One B-rep face of a CAD part: STEP entity #314.
In plain terms, the planar face has unit normal (1, 0, 0).
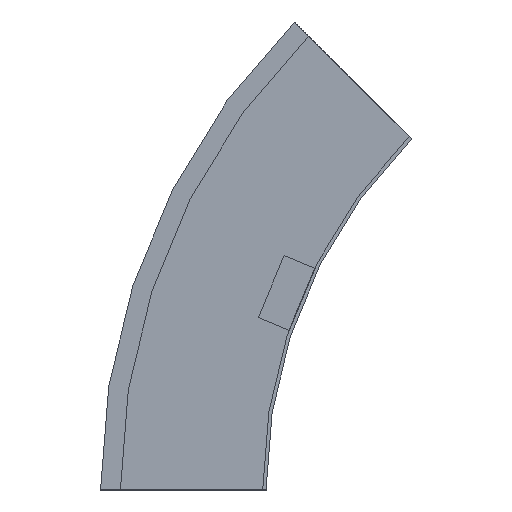
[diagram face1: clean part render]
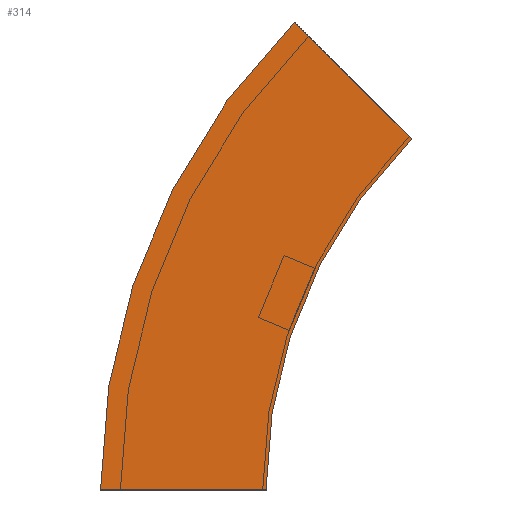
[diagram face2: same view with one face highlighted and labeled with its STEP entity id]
Its self-contained STEP definition (entity closure, numbers rounded to 3 decimals):
#16 = LINE ( 'NONE', #285, #551 ) ;
#46 = CARTESIAN_POINT ( 'NONE',  ( 0., 0., 0. ) ) ;
#48 = ORIENTED_EDGE ( 'NONE', *, *, #304, .F. ) ;
#53 = AXIS2_PLACEMENT_3D ( 'NONE', #159, #334, #133 ) ;
#73 = EDGE_LOOP ( 'NONE', ( #298, #48, #467, #95 ) ) ;
#92 = DIRECTION ( 'NONE',  ( 0., 1., 0. ) ) ;
#95 = ORIENTED_EDGE ( 'NONE', *, *, #448, .T. ) ;
#106 = CARTESIAN_POINT ( 'NONE',  ( 0., -300., 0. ) ) ;
#133 = DIRECTION ( 'NONE',  ( 0., 0., -1. ) ) ;
#159 = CARTESIAN_POINT ( 'NONE',  ( 0., 0., 0. ) ) ;
#161 = VERTEX_POINT ( 'NONE', #366 ) ;
#172 = EDGE_CURVE ( 'NONE', #510, #161, #173, .T. ) ;
#173 = CIRCLE ( 'NONE', #198, 400. ) ;
#198 = AXIS2_PLACEMENT_3D ( 'NONE', #370, #544, #543 ) ;
#210 = CIRCLE ( 'NONE', #527, 300. ) ;
#285 = CARTESIAN_POINT ( 'NONE',  ( 0., -87.868, 212.132 ) ) ;
#298 = ORIENTED_EDGE ( 'NONE', *, *, #172, .T. ) ;
#304 = EDGE_CURVE ( 'NONE', #531, #161, #16, .T. ) ;
#314 = ADVANCED_FACE ( 'NONE', ( #415 ), #376, .T. ) ;
#324 = CARTESIAN_POINT ( 'NONE',  ( 0., -87.868, 212.132 ) ) ;
#334 = DIRECTION ( 'NONE',  ( 1., 0., 0. ) ) ;
#339 = DIRECTION ( 'NONE',  ( 0., 0.707, 0.707 ) ) ;
#366 = CARTESIAN_POINT ( 'NONE',  ( 0., -17.157, 282.843 ) ) ;
#370 = CARTESIAN_POINT ( 'NONE',  ( 0., -300., 0. ) ) ;
#376 = PLANE ( 'NONE',  #53 ) ;
#399 = VECTOR ( 'NONE', #92, 1000. ) ;
#400 = DIRECTION ( 'NONE',  ( 0., 1., 0. ) ) ;
#404 = VERTEX_POINT ( 'NONE', #542 ) ;
#415 = FACE_OUTER_BOUND ( 'NONE', #73, .T. ) ;
#448 = EDGE_CURVE ( 'NONE', #404, #510, #487, .T. ) ;
#467 = ORIENTED_EDGE ( 'NONE', *, *, #471, .F. ) ;
#471 = EDGE_CURVE ( 'NONE', #404, #531, #210, .T. ) ;
#487 = LINE ( 'NONE', #46, #399 ) ;
#504 = DIRECTION ( 'NONE',  ( 1., 0., 0. ) ) ;
#510 = VERTEX_POINT ( 'NONE', #537 ) ;
#527 = AXIS2_PLACEMENT_3D ( 'NONE', #106, #504, #400 ) ;
#531 = VERTEX_POINT ( 'NONE', #324 ) ;
#537 = CARTESIAN_POINT ( 'NONE',  ( 0., 100., 0. ) ) ;
#542 = CARTESIAN_POINT ( 'NONE',  ( 0., 0., 0. ) ) ;
#543 = DIRECTION ( 'NONE',  ( 0., 1., 0. ) ) ;
#544 = DIRECTION ( 'NONE',  ( 1., 0., 0. ) ) ;
#551 = VECTOR ( 'NONE', #339, 1000. ) ;
